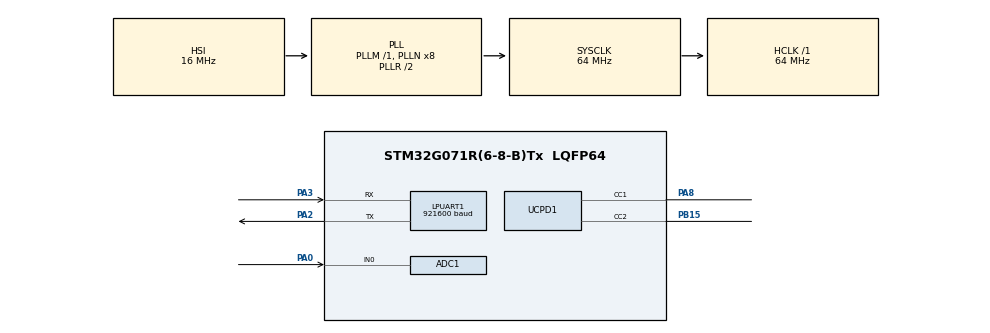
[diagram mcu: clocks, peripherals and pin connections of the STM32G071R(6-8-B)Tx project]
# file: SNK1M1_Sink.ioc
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ADC1.ClockPrescaler=ADC_CLOCK_SYNC_PCLK_DIV4
ADC1.ContinuousConvMode=ENABLE
ADC1.NbrOfConversion=1
ADC1.NbrOfConversionFlag=0
ADC1.Overrun=ADC_OVR_DATA_OVERWRITTEN
ADC1.SamplingTimeCommon1=ADC_SAMPLETIME_160CYCLES_5
ADC1.SelectedChannel=ADC_CHANNEL_0
ADC1.Sequencer=NOT_FULLY_CONFIGURABLE
ADC1.master=1
Dma.LPUART1_TX.2.Direction=DMA_MEMORY_TO_PERIPH
Dma.LPUART1_TX.2.EventEnable=DISABLE
Dma.LPUART1_TX.2.Instance=DMA1_Channel3
Dma.LPUART1_TX.2.MemDataAlignment=DMA_MDATAALIGN_BYTE
Dma.LPUART1_TX.2.MemInc=DMA_MINC_ENABLE
Dma.LPUART1_TX.2.Mode=DMA_NORMAL
Dma.LPUART1_TX.2.PeriphDataAlignment=DMA_PDATAALIGN_BYTE
Dma.LPUART1_TX.2.PeriphInc=DMA_PINC_DISABLE
Dma.LPUART1_TX.2.Polarity=HAL_DMAMUX_REQ_GEN_RISING
Dma.LPUART1_TX.2.Priority=DMA_PRIORITY_LOW
Dma.LPUART1_TX.2.RequestNumber=1
Dma.LPUART1_TX.2.SignalID=NONE
Dma.LPUART1_TX.2.SyncEnable=DISABLE
Dma.LPUART1_TX.2.SyncPolarity=HAL_DMAMUX_SYNC_NO_EVENT
Dma.LPUART1_TX.2.SyncRequestNumber=1
Dma.LPUART1_TX.2.SyncSignalID=NONE
Dma.Request0=UCPD1_RX
Dma.Request1=UCPD1_TX
Dma.Request2=LPUART1_TX
Dma.UCPD1_RX.0.Direction=DMA_PERIPH_TO_MEMORY
Dma.UCPD1_RX.0.EventEnable=DISABLE
Dma.UCPD1_RX.0.Instance=DMA1_Channel4
Dma.UCPD1_RX.0.MemDataAlignment=DMA_MDATAALIGN_BYTE
Dma.UCPD1_RX.0.MemInc=DMA_MINC_ENABLE
Dma.UCPD1_RX.0.Mode=DMA_NORMAL
Dma.UCPD1_RX.0.PeriphDataAlignment=DMA_PDATAALIGN_BYTE
Dma.UCPD1_RX.0.PeriphInc=DMA_PINC_DISABLE
Dma.UCPD1_RX.0.Polarity=HAL_DMAMUX_REQ_GEN_RISING
Dma.UCPD1_RX.0.Priority=DMA_PRIORITY_LOW
Dma.UCPD1_RX.0.RequestNumber=1
Dma.UCPD1_RX.0.SignalID=NONE
Dma.UCPD1_RX.0.SyncEnable=DISABLE
Dma.UCPD1_RX.0.SyncPolarity=HAL_DMAMUX_SYNC_NO_EVENT
Dma.UCPD1_RX.0.SyncRequestNumber=1
Dma.UCPD1_RX.0.SyncSignalID=NONE
Dma.UCPD1_TX.1.Direction=DMA_MEMORY_TO_PERIPH
Dma.UCPD1_TX.1.EventEnable=DISABLE
Dma.UCPD1_TX.1.Instance=DMA1_Channel2
Dma.UCPD1_TX.1.MemDataAlignment=DMA_MDATAALIGN_BYTE
Dma.UCPD1_TX.1.MemInc=DMA_MINC_ENABLE
Dma.UCPD1_TX.1.Mode=DMA_NORMAL
Dma.UCPD1_TX.1.PeriphDataAlignment=DMA_PDATAALIGN_BYTE
Dma.UCPD1_TX.1.PeriphInc=DMA_PINC_DISABLE
Dma.UCPD1_TX.1.Polarity=HAL_DMAMUX_REQ_GEN_RISING
Dma.UCPD1_TX.1.Priority=DMA_PRIORITY_LOW
Dma.UCPD1_TX.1.RequestNumber=1
Dma.UCPD1_TX.1.SignalID=NONE
Dma.UCPD1_TX.1.SyncEnable=DISABLE
Dma.UCPD1_TX.1.SyncPolarity=HAL_DMAMUX_SYNC_NO_EVENT
Dma.UCPD1_TX.1.SyncRequestNumber=1
Dma.UCPD1_TX.1.SyncSignalID=NONE
FREERTOS.INCLUDE_eTaskGetState=1
FREERTOS.Tasks01=defaultTask,0,128,StartDefaultTask,Default,NULL,Dynamic,NULL,NULL
FREERTOS.configTOTAL_HEAP_SIZE=7000
GUI_INTERFACE.HWBoardVersionName=NUCLEO-G071RB
GUI_INTERFACE.PDTypeName=SNK1M1
LPUART1.BaudRate=921600
Mcu.Family=STM32G0
Mcu.Name=STM32G071R(6-8-B)Tx
Mcu.Package=LQFP64
NVIC.DMA1_Ch4_7_DMAMUX1_OVR_IRQn=true\:3\:0\:false\:false\:true\:false\:false\:true\:true
NVIC.DMA1_Channel2_3_IRQn=true\:3\:0\:false\:false\:true\:true\:false\:true\:true
NVIC.UCPD1_2_IRQn=true\:3\:0\:false\:false\:true\:true\:true\:false\:true
NVIC.USART3_4_LPUART1_IRQn=true\:3\:0\:false\:false\:true\:true\:true\:true\:true
PA0.Mode=IN0
PA0.Signal=ADC1_IN0
PA2.Mode=Asynchronous
PA2.Signal=LPUART1_TX
PA3.Mode=Asynchronous
PA3.Signal=LPUART1_RX
PA8.Mode=Sink_AllSignals
PA8.Signal=UCPD1_CC1
PB15.Mode=Sink_AllSignals
PB15.Signal=UCPD1_CC2
ProjectManager.HeapSize=0xC00
ProjectManager.StackSize=0x400
ProjectManager.TargetToolchain=STM32CubeIDE
RCC.ADCFreq_Value=64000000
RCC.AHBFreq_Value=64000000
RCC.CortexFreq_Value=64000000
RCC.EXTERNAL_CLOCK_VALUE=12288000
RCC.HCLKFreq_Value=64000000
RCC.HSE_VALUE=8000000
RCC.HSI_VALUE=16000000
RCC.LSE_VALUE=32768
RCC.SYSCLKFreq_VALUE=64000000
RCC.SYSCLKSource=RCC_SYSCLKSOURCE_PLLCLK
RCC.VCOOutputFreq_Value=128000000
STMicroelectronics.X-CUBE-TCPP.4.1.0.NucleoIiSTM32G0xxCcBoardOoSupportJjSTM32G0xxIiNucleoJjCommon=true
STMicroelectronics.X-CUBE-TCPP.4.1.0.SNK1M1CcBoardOoSupportJjXAaNUCLEOAaSNK1M1JjCommon=true
STMicroelectronics.X-CUBE-TCPP.4.1.0.TCPP01CcBoardOoPartJjTCPP01JjTCPP01=true
STMicroelectronics.X-CUBE-TCPP.4.1.0.USBPDOoApplicationCcDeviceJjApplication=Sink
STMicroelectronics.X-CUBE-TCPP.4.1.0.XAaNUCLEOAaSNK1M1CcBoardOoSupportJjXAaNUCLEOAaSNK1M1JjCommon=true
STMicroelectronics.X-CUBE-TCPP.4.1.0.tcpp01CcBoardOoPartJjtcpp01Jjtcpp01=true
USBPD.PE_DR_Swap_To_DFP_P0=USBPD_FALSE
USBPD.PE_DR_Swap_To_UFP_P0=USBPD_FALSE
USBPD.PE_SpecRevision_P0=USBPD_SPECIFICATION_REV3
USBPD.PORT0_NB_SINKPDO=4
USBPD.PORT0_SINK_PDO1=0x00019096
USBPD.PORT0_SINK_PDO2=0x0002D12C
USBPD.PORT0_SINK_PDO3=0x0004B0C8
USBPD.PORT0_SINK_PDO4=0x0006412C
VP_FREERTOS_VS_CMSIS_V1.Mode=CMSIS_V1
VP_GUI_INTERFACE_VS_gui_interface.Mode=GUI_INTERFACE
VP_STMicroelectronics.X-CUBE-TCPP_VS_BoardOoPartJjtcpp01_4.1.0_4.1.0.Mode=BoardOoPartJjtcpp01
VP_STMicroelectronics.X-CUBE-TCPP_VS_BoardOoSupportJjXAaNUCLEOAaSNK1M1_4.1.0_4.1.0.Mode=BoardOoSupportJjXAaNUCLEOAaSNK1M1
VP_STMicroelectronics.X-CUBE-TCPP_VS_DeviceJjUSBPDOoApplication_4.1.0_4.1.0.Mode=DeviceJjUSBPDOoApplication
VP_SYS_VS_DBSignals.Mode=DisableDeadBatterySignals
VP_TRACER_EMB_VS_traceremb_lpuart1.Mode=TRACER_EMB_LPUART1
VP_USBPD_VS_PD3FULL.Mode=PD3_Full_Stack
VP_USBPD_VS_USBPD1.Mode=USBPD_P0
VP_USBPD_VS_usbpd_tim1.Mode=TIM1
VP_USBPD_VS_usbpd_traceremb.Mode=TRACER_EMB
board=NUCLEO-G071RB

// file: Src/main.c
/* USER CODE BEGIN Header */
/**
  ******************************************************************************
  * @file           : main.c
  * @brief          : Main program body
  ******************************************************************************
  * @attention
  *
  * Copyright (c) 2021 STMicroelectronics.
  * All rights reserved.
  *
  * This software is licensed under terms that can be found in the LICENSE file
  * in the root directory of this software component.
  * If no LICENSE file comes with this software, it is provided AS-IS.
  *
  ******************************************************************************
  */
/* USER CODE END Header */
#include "main.h"
#include "cmsis_os.h"
#include "usbpd.h"

ADC_HandleTypeDef hadc1;

osThreadId defaultTaskHandle;

void SystemClock_Config(void);
static void MX_GPIO_Init(void);
static void MX_DMA_Init(void);
static void MX_ADC1_Init(void);
static void MX_UCPD1_Init(void);
static void MX_LPUART1_UART_Init(void);
void StartDefaultTask(void const * argument);

int main(void)
{

  /* MCU Configuration--------------------------------------------------------*/

  /* Reset of all peripherals, Initializes the Flash interface and the Systick. */
  HAL_Init();

  /* Configure the system clock */
  SystemClock_Config();

  /* Initialize all configured peripherals */
  MX_GPIO_Init();
  MX_DMA_Init();
  MX_ADC1_Init();
  MX_UCPD1_Init();
  MX_LPUART1_UART_Init();

  /* USBPD initialisation ---------------------------------*/
  MX_USBPD_Init();

  /* Create the thread(s) */
  /* definition and creation of defaultTask */
  osThreadDef(defaultTask, StartDefaultTask, osPriorityNormal, 0, 128);
  defaultTaskHandle = osThreadCreate(osThread(defaultTask), NULL);

  /* Start scheduler */
  osKernelStart();

  /* We should never get here as control is now taken by the scheduler */
  /* Infinite loop */
  while (1)
  {

  }
}

void SystemClock_Config(void)
{
  RCC_OscInitTypeDef RCC_OscInitStruct = {0};
  RCC_ClkInitTypeDef RCC_ClkInitStruct = {0};

  /** Configure the main internal regulator output voltage
  */
  HAL_PWREx_ControlVoltageScaling(PWR_REGULATOR_VOLTAGE_SCALE1);
  /** Initializes the RCC Oscillators according to the specified parameters
  * in the RCC_OscInitTypeDef structure.
  */
  RCC_OscInitStruct.OscillatorType = RCC_OSCILLATORTYPE_HSI;
  RCC_OscInitStruct.HSIState = RCC_HSI_ON;
  RCC_OscInitStruct.HSIDiv = RCC_HSI_DIV1;
  RCC_OscInitStruct.HSICalibrationValue = RCC_HSICALIBRATION_DEFAULT;
  RCC_OscInitStruct.PLL.PLLState = RCC_PLL_ON;
  RCC_OscInitStruct.PLL.PLLSource = RCC_PLLSOURCE_HSI;
  RCC_OscInitStruct.PLL.PLLM = RCC_PLLM_DIV1;
  RCC_OscInitStruct.PLL.PLLN = 8;
  RCC_OscInitStruct.PLL.PLLP = RCC_PLLP_DIV2;
  RCC_OscInitStruct.PLL.PLLQ = RCC_PLLQ_DIV2;
  RCC_OscInitStruct.PLL.PLLR = RCC_PLLR_DIV2;
  if (HAL_RCC_OscConfig(&RCC_OscInitStruct) != HAL_OK)
  {
    Error_Handler();
  }
  /** Initializes the CPU, AHB and APB buses clocks
  */
  RCC_ClkInitStruct.ClockType = RCC_CLOCKTYPE_HCLK|RCC_CLOCKTYPE_SYSCLK
                              |RCC_CLOCKTYPE_PCLK1;
  RCC_ClkInitStruct.SYSCLKSource = RCC_SYSCLKSOURCE_PLLCLK;
  RCC_ClkInitStruct.AHBCLKDivider = RCC_SYSCLK_DIV1;
  RCC_ClkInitStruct.APB1CLKDivider = RCC_HCLK_DIV1;

  if (HAL_RCC_ClockConfig(&RCC_ClkInitStruct, FLASH_LATENCY_2) != HAL_OK)
  {
    Error_Handler();
  }
}

static void MX_ADC1_Init(void)
{

  ADC_ChannelConfTypeDef sConfig = {0};

  /** Configure the global features of the ADC (Clock, Resolution, Data Alignment and number of conversion)
  */
  hadc1.Instance = ADC1;
  hadc1.Init.ClockPrescaler = ADC_CLOCK_SYNC_PCLK_DIV4;
  hadc1.Init.Resolution = ADC_RESOLUTION_12B;
  hadc1.Init.DataAlign = ADC_DATAALIGN_RIGHT;
  hadc1.Init.ScanConvMode = ADC_SCAN_DISABLE;
  hadc1.Init.EOCSelection = ADC_EOC_SINGLE_CONV;
  hadc1.Init.LowPowerAutoWait = DISABLE;
  hadc1.Init.LowPowerAutoPowerOff = DISABLE;
  hadc1.Init.ContinuousConvMode = ENABLE;
  hadc1.Init.NbrOfConversion = 1;
  hadc1.Init.DiscontinuousConvMode = DISABLE;
  hadc1.Init.ExternalTrigConv = ADC_SOFTWARE_START;
  hadc1.Init.ExternalTrigConvEdge = ADC_EXTERNALTRIGCONVEDGE_NONE;
  hadc1.Init.DMAContinuousRequests = DISABLE;
  hadc1.Init.Overrun = ADC_OVR_DATA_OVERWRITTEN;
  hadc1.Init.SamplingTimeCommon1 = ADC_SAMPLETIME_160CYCLES_5;
  hadc1.Init.SamplingTimeCommon2 = ADC_SAMPLETIME_160CYCLES_5;
  hadc1.Init.OversamplingMode = DISABLE;
  hadc1.Init.TriggerFrequencyMode = ADC_TRIGGER_FREQ_HIGH;
  if (HAL_ADC_Init(&hadc1) != HAL_OK)
  {
    Error_Handler();
  }
  /** Configure Regular Channel
  */
  sConfig.Channel = ADC_CHANNEL_9;
  sConfig.Rank = ADC_REGULAR_RANK_1;
  sConfig.SamplingTime = ADC_SAMPLINGTIME_COMMON_1;
  if (HAL_ADC_ConfigChannel(&hadc1, &sConfig) != HAL_OK)
  {
    Error_Handler();
  }
  /* USER CODE BEGIN ADC1_Init 2 */
  HAL_ADCEx_Calibration_Start(&hadc1);
  HAL_ADC_Start(&hadc1);
  /* USER CODE END ADC1_Init 2 */

}

static void MX_LPUART1_UART_Init(void)
{

  LL_LPUART_InitTypeDef LPUART_InitStruct = {0};

  LL_GPIO_InitTypeDef GPIO_InitStruct = {0};
  RCC_PeriphCLKInitTypeDef PeriphClkInit = {0};

  /** Initializes the peripherals clocks
  */
  PeriphClkInit.PeriphClockSelection = RCC_PERIPHCLK_LPUART1;
  PeriphClkInit.Lpuart1ClockSelection = RCC_LPUART1CLKSOURCE_PCLK1;
  if (HAL_RCCEx_PeriphCLKConfig(&PeriphClkInit) != HAL_OK)
  {
    Error_Handler();
  }

  /* Peripheral clock enable */
  LL_APB1_GRP1_EnableClock(LL_APB1_GRP1_PERIPH_LPUART1);

  LL_IOP_GRP1_EnableClock(LL_IOP_GRP1_PERIPH_GPIOA);
  /**LPUART1 GPIO Configuration
  PA2   ------> LPUART1_TX
  PA3   ------> LPUART1_RX
  */
  GPIO_InitStruct.Pin = LL_GPIO_PIN_2;
  GPIO_InitStruct.Mode = LL_GPIO_MODE_ALTERNATE;
  GPIO_InitStruct.Speed = LL_GPIO_SPEED_FREQ_LOW;
  GPIO_InitStruct.OutputType = LL_GPIO_OUTPUT_PUSHPULL;
  GPIO_InitStruct.Pull = LL_GPIO_PULL_NO;
  GPIO_InitStruct.Alternate = LL_GPIO_AF_6;
  LL_GPIO_Init(GPIOA, &GPIO_InitStruct);

  GPIO_InitStruct.Pin = LL_GPIO_PIN_3;
  GPIO_InitStruct.Mode = LL_GPIO_MODE_ALTERNATE;
  GPIO_InitStruct.Speed = LL_GPIO_SPEED_FREQ_LOW;
  GPIO_InitStruct.OutputType = LL_GPIO_OUTPUT_PUSHPULL;
  GPIO_InitStruct.Pull = LL_GPIO_PULL_NO;
  GPIO_InitStruct.Alternate = LL_GPIO_AF_6;
  LL_GPIO_Init(GPIOA, &GPIO_InitStruct);

  /* LPUART1 DMA Init */

  /* LPUART1_TX Init */
  LL_DMA_SetPeriphRequest(DMA1, LL_DMA_CHANNEL_3, LL_DMAMUX_REQ_LPUART1_TX);

  LL_DMA_SetDataTransferDirection(DMA1, LL_DMA_CHANNEL_3, LL_DMA_DIRECTION_MEMORY_TO_PERIPH);

  LL_DMA_SetChannelPriorityLevel(DMA1, LL_DMA_CHANNEL_3, LL_DMA_PRIORITY_LOW);

  LL_DMA_SetMode(DMA1, LL_DMA_CHANNEL_3, LL_DMA_MODE_NORMAL);

  LL_DMA_SetPeriphIncMode(DMA1, LL_DMA_CHANNEL_3, LL_DMA_PERIPH_NOINCREMENT);

  LL_DMA_SetMemoryIncMode(DMA1, LL_DMA_CHANNEL_3, LL_DMA_MEMORY_INCREMENT);

  LL_DMA_SetPeriphSize(DMA1, LL_DMA_CHANNEL_3, LL_DMA_PDATAALIGN_BYTE);

  LL_DMA_SetMemorySize(DMA1, LL_DMA_CHANNEL_3, LL_DMA_MDATAALIGN_BYTE);

  /* LPUART1 interrupt Init */
  NVIC_SetPriority(USART3_4_LPUART1_IRQn, 3);
  NVIC_EnableIRQ(USART3_4_LPUART1_IRQn);

  LPUART_InitStruct.PrescalerValue = LL_LPUART_PRESCALER_DIV1;
  LPUART_InitStruct.BaudRate = 921600;
  LPUART_InitStruct.DataWidth = LL_LPUART_DATAWIDTH_8B;
  LPUART_InitStruct.StopBits = LL_LPUART_STOPBITS_1;
  LPUART_InitStruct.Parity = LL_LPUART_PARITY_NONE;
  LPUART_InitStruct.TransferDirection = LL_LPUART_DIRECTION_TX_RX;
  LPUART_InitStruct.HardwareFlowControl = LL_LPUART_HWCONTROL_NONE;
  LL_LPUART_Init(LPUART1, &LPUART_InitStruct);
  LL_LPUART_SetTXFIFOThreshold(LPUART1, LL_LPUART_FIFOTHRESHOLD_1_8);
  LL_LPUART_SetRXFIFOThreshold(LPUART1, LL_LPUART_FIFOTHRESHOLD_1_8);
  LL_LPUART_DisableFIFO(LPUART1);

  LL_LPUART_Enable(LPUART1);

  /* Polling LPUART1 initialisation */
  while((!(LL_LPUART_IsActiveFlag_TEACK(LPUART1))) || (!(LL_LPUART_IsActiveFlag_REACK(LPUART1))))
  {
  }

}

static void MX_UCPD1_Init(void)
{

  LL_GPIO_InitTypeDef GPIO_InitStruct = {0};

  /* Peripheral clock enable */
  LL_APB1_GRP1_EnableClock(LL_APB1_GRP1_PERIPH_UCPD1);

  LL_IOP_GRP1_EnableClock(LL_IOP_GRP1_PERIPH_GPIOB);
  LL_IOP_GRP1_EnableClock(LL_IOP_GRP1_PERIPH_GPIOA);
  /**UCPD1 GPIO Configuration
  PB15   ------> UCPD1_CC2
  PA8   ------> UCPD1_CC1
  */
  GPIO_InitStruct.Pin = LL_GPIO_PIN_15;
  GPIO_InitStruct.Mode = LL_GPIO_MODE_ANALOG;
  GPIO_InitStruct.Pull = LL_GPIO_PULL_NO;
  LL_GPIO_Init(GPIOB, &GPIO_InitStruct);

  GPIO_InitStruct.Pin = LL_GPIO_PIN_8;
  GPIO_InitStruct.Mode = LL_GPIO_MODE_ANALOG;
  GPIO_InitStruct.Pull = LL_GPIO_PULL_NO;
  LL_GPIO_Init(GPIOA, &GPIO_InitStruct);

  /* UCPD1 DMA Init */

  /* UCPD1_RX Init */
  LL_DMA_SetPeriphRequest(DMA1, LL_DMA_CHANNEL_1, LL_DMAMUX_REQ_UCPD1_RX);

  LL_DMA_SetDataTransferDirection(DMA1, LL_DMA_CHANNEL_1, LL_DMA_DIRECTION_PERIPH_TO_MEMORY);

  LL_DMA_SetChannelPriorityLevel(DMA1, LL_DMA_CHANNEL_1, LL_DMA_PRIORITY_LOW);

  LL_DMA_SetMode(DMA1, LL_DMA_CHANNEL_1, LL_DMA_MODE_NORMAL);

  LL_DMA_SetPeriphIncMode(DMA1, LL_DMA_CHANNEL_1, LL_DMA_PERIPH_NOINCREMENT);

  LL_DMA_SetMemoryIncMode(DMA1, LL_DMA_CHANNEL_1, LL_DMA_MEMORY_INCREMENT);

  LL_DMA_SetPeriphSize(DMA1, LL_DMA_CHANNEL_1, LL_DMA_PDATAALIGN_BYTE);

  LL_DMA_SetMemorySize(DMA1, LL_DMA_CHANNEL_1, LL_DMA_MDATAALIGN_BYTE);

  /* UCPD1_TX Init */
  LL_DMA_SetPeriphRequest(DMA1, LL_DMA_CHANNEL_2, LL_DMAMUX_REQ_UCPD1_TX);

  LL_DMA_SetDataTransferDirection(DMA1, LL_DMA_CHANNEL_2, LL_DMA_DIRECTION_MEMORY_TO_PERIPH);

  LL_DMA_SetChannelPriorityLevel(DMA1, LL_DMA_CHANNEL_2, LL_DMA_PRIORITY_LOW);

  LL_DMA_SetMode(DMA1, LL_DMA_CHANNEL_2, LL_DMA_MODE_NORMAL);

  LL_DMA_SetPeriphIncMode(DMA1, LL_DMA_CHANNEL_2, LL_DMA_PERIPH_NOINCREMENT);

  LL_DMA_SetMemoryIncMode(DMA1, LL_DMA_CHANNEL_2, LL_DMA_MEMORY_INCREMENT);

  LL_DMA_SetPeriphSize(DMA1, LL_DMA_CHANNEL_2, LL_DMA_PDATAALIGN_BYTE);

  LL_DMA_SetMemorySize(DMA1, LL_DMA_CHANNEL_2, LL_DMA_MDATAALIGN_BYTE);

  /* UCPD1 interrupt Init */
  NVIC_SetPriority(UCPD1_2_IRQn, 3);
  NVIC_EnableIRQ(UCPD1_2_IRQn);

}

static void MX_DMA_Init(void)
{

  /* DMA controller clock enable */
  __HAL_RCC_DMA1_CLK_ENABLE();

  /* DMA interrupt init */
  /* DMA1_Channel1_IRQn interrupt configuration */
  NVIC_SetPriority(DMA1_Channel1_IRQn, 3);
  NVIC_EnableIRQ(DMA1_Channel1_IRQn);
  /* DMA1_Channel2_3_IRQn interrupt configuration */
  NVIC_SetPriority(DMA1_Channel2_3_IRQn, 3);
  NVIC_EnableIRQ(DMA1_Channel2_3_IRQn);

}

static void MX_GPIO_Init(void)
{
  GPIO_InitTypeDef GPIO_InitStruct = {0};

  /* GPIO Ports Clock Enable */
  __HAL_RCC_GPIOA_CLK_ENABLE();
  __HAL_RCC_GPIOB_CLK_ENABLE();
  __HAL_RCC_GPIOC_CLK_ENABLE();

  /*Configure GPIO pin Output Level */
  HAL_GPIO_WritePin(DB_OUT_GPIO_Port, DB_OUT_Pin, GPIO_PIN_SET);

  /*Configure GPIO pin Output Level */
  HAL_GPIO_WritePin(VCC_OUT_GPIO_Port, VCC_OUT_Pin, GPIO_PIN_SET);

  /*Configure GPIO pin : DB_OUT_Pin */
  GPIO_InitStruct.Pin = DB_OUT_Pin;
  GPIO_InitStruct.Mode = GPIO_MODE_OUTPUT_PP;
  GPIO_InitStruct.Pull = GPIO_NOPULL;
  GPIO_InitStruct.Speed = GPIO_SPEED_FREQ_LOW;
  HAL_GPIO_Init(DB_OUT_GPIO_Port, &GPIO_InitStruct);

  /*Configure GPIO pin : VCC_OUT_Pin */
  GPIO_InitStruct.Pin = VCC_OUT_Pin;
  GPIO_InitStruct.Mode = GPIO_MODE_OUTPUT_PP;
  GPIO_InitStruct.Pull = GPIO_NOPULL;
  GPIO_InitStruct.Speed = GPIO_SPEED_FREQ_LOW;
  HAL_GPIO_Init(VCC_OUT_GPIO_Port, &GPIO_InitStruct);

}

void StartDefaultTask(void const * argument)
{
  for(;;)
  {
    osDelay(1);
  }
}

void Error_Handler(void)
{
  __disable_irq();
  while (1)
  {
  }
}
